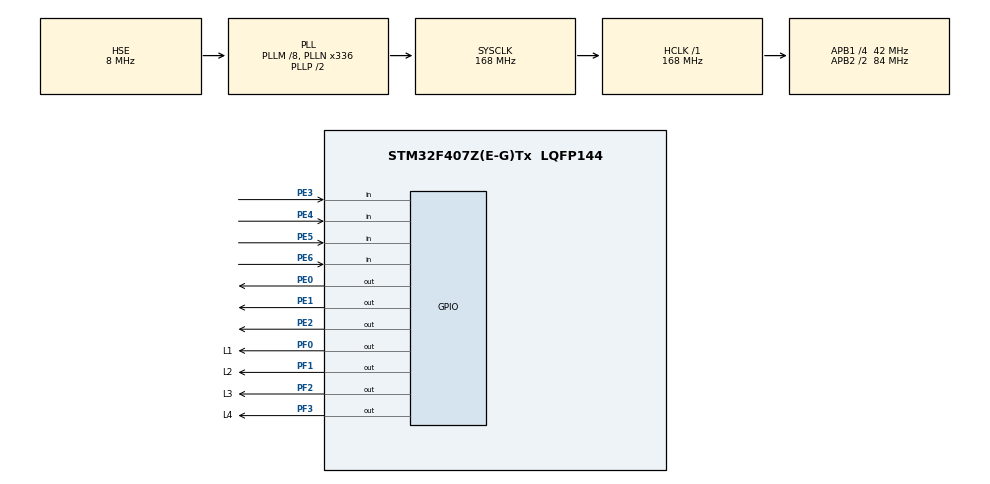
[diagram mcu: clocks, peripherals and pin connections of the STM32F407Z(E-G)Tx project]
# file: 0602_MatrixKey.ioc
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Mcu.Family=STM32F4
Mcu.Name=STM32F407Z(E-G)Tx
Mcu.Package=LQFP144
NVIC.PriorityGroup=NVIC_PRIORITYGROUP_4
PA13.Mode=Serial_Wire
PA13.Signal=SYS_JTMS-SWDIO
PA14.Mode=Serial_Wire
PA14.Signal=SYS_JTCK-SWCLK
PE0.PinState=GPIO_PIN_SET
PE0.Signal=GPIO_Output
PE1.PinState=GPIO_PIN_SET
PE1.Signal=GPIO_Output
PE2.PinState=GPIO_PIN_SET
PE2.Signal=GPIO_Output
PE3.GPIO_PuPd=GPIO_PULLUP
PE3.Signal=GPIO_Input
PE4.GPIO_PuPd=GPIO_PULLUP
PE4.Signal=GPIO_Input
PE5.GPIO_PuPd=GPIO_PULLUP
PE5.Signal=GPIO_Input
PE6.GPIO_PuPd=GPIO_PULLUP
PE6.Signal=GPIO_Input
PF0.GPIO_Label=L1
PF0.PinState=GPIO_PIN_SET
PF0.Signal=GPIO_Output
PF1.GPIO_Label=L2
PF1.PinState=GPIO_PIN_SET
PF1.Signal=GPIO_Output
PF2.GPIO_Label=L3
PF2.PinState=GPIO_PIN_SET
PF2.Signal=GPIO_Output
PF3.GPIO_Label=L4
PF3.PinState=GPIO_PIN_SET
PF3.Signal=GPIO_Output
PH0-OSC_IN.Mode=HSE-External-Oscillator
PH0-OSC_IN.Signal=RCC_OSC_IN
PH1-OSC_OUT.Mode=HSE-External-Oscillator
PH1-OSC_OUT.Signal=RCC_OSC_OUT
ProjectManager.HeapSize=0x200
ProjectManager.StackSize=0x400
ProjectManager.TargetToolchain=STM32CubeIDE
RCC.48MHZClocksFreq_Value=84000000
RCC.AHBFreq_Value=168000000
RCC.APB1CLKDivider=RCC_HCLK_DIV4
RCC.APB1Freq_Value=42000000
RCC.APB1TimFreq_Value=84000000
RCC.APB2CLKDivider=RCC_HCLK_DIV2
RCC.APB2Freq_Value=84000000
RCC.APB2TimFreq_Value=168000000
RCC.CortexFreq_Value=168000000
RCC.HCLKFreq_Value=168000000
RCC.HSE_VALUE=8000000
RCC.HSI_VALUE=16000000
RCC.LSE_VALUE=32768
RCC.PLLM=4
RCC.PLLN=168
RCC.PLLSourceVirtual=RCC_PLLSOURCE_HSE
RCC.SYSCLKFreq_VALUE=168000000
RCC.SYSCLKSource=RCC_SYSCLKSOURCE_PLLCLK
RCC.VCOOutputFreq_Value=336000000
board=custom

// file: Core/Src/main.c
/* USER CODE BEGIN Header */
/**
  ******************************************************************************
  * @file           : main.c
  * @brief          : 0602 MatrixKey 3×4矩阵键盘 → PF口LED输出421‑BCD
  *                 行：PE4 PE5 PE6    列：PE0 PE1 PE2 PE3
  *                 PF0~PF3 BCD输出，LED低电平点亮
  ******************************************************************************
  */
/* USER CODE END Header */
#include "main.h"

/* USER CODE BEGIN PV */
static uint8_t KeyVal = 0;
/* USER CODE END PV */

void SystemClock_Config(void);
static void MX_GPIO_Init(void);
/* USER CODE BEGIN PFP */
static void MatrixKey_Scan(void);
/* USER CODE END PFP */

/* USER CODE BEGIN 0 */

/**
 * @brief 3×4矩阵键盘扫描
 * 行：PE4、PE5、PE6
 * 列：PE0、PE1、PE2、PE3（上拉输入）
 * PF0-PF3输出BCD，低电平点亮LED
 */
static void MatrixKey_Scan(void)
{
    uint8_t i;
    uint16_t colState;

    // 依次扫描3行
    for(i = 0; i < 3; i++)
    {
        // 全部行先拉高
        HAL_GPIO_WritePin(GPIOE, GPIO_PIN_4|GPIO_PIN_5|GPIO_PIN_6, GPIO_PIN_SET);
        // 拉低当前行
        if(i == 0) HAL_GPIO_WritePin(GPIOE, GPIO_PIN_4, GPIO_PIN_RESET);
        if(i == 1) HAL_GPIO_WritePin(GPIOE, GPIO_PIN_5, GPIO_PIN_RESET);
        if(i == 2) HAL_GPIO_WritePin(GPIOE, GPIO_PIN_6, GPIO_PIN_RESET);

        HAL_Delay(5);
        colState = GPIOE->IDR & 0x0FU;

        if(colState != 0x0FU)
        {
            HAL_Delay(16);  //消抖
            colState = GPIOE->IDR & 0x0FU;
            if(colState != 0x0FU)
            {
                switch(colState)
                {
                    case 0x0E: KeyVal = i*4 + 1; break;  //PE0按下
                    case 0x0D: KeyVal = i*4 + 2; break;  //PE1按下
                    case 0x0B: KeyVal = i*4 + 3; break;  //PE2按下
                    case 0x07: KeyVal = i*4 + 4; break;  //PE3按下
                    default: break;
                }
                //等待松手
                while( (GPIOE->IDR & 0x0FU) != 0x0FU );
                HAL_Delay(10);
            }
        }
    }

    // PF4~PF7保持不变，PF0~PF3输出BCD，低亮
    GPIOF->ODR = (GPIOF->ODR & 0xF0U) | ( ~KeyVal & 0x0FU );
}

/* USER CODE END 0 */

int main(void)
{

  /* MCU Configuration--------------------------------------------------------*/

  /* Reset of all peripherals, Initializes the Flash interface and the Systick. */
  HAL_Init();

  /* Configure the system clock */
  SystemClock_Config();

  /* Initialize all configured peripherals */
  MX_GPIO_Init();

  /* Infinite loop */
  /* USER CODE BEGIN WHILE */
  while (1)
  {
    MatrixKey_Scan();
    /* USER CODE END WHILE */

  }
}

void SystemClock_Config(void)
{
  RCC_OscInitTypeDef RCC_OscInitStruct = {0};
  RCC_ClkInitTypeDef RCC_ClkInitStruct = {0};

  __HAL_RCC_PWR_CLK_ENABLE();
  __HAL_PWR_VOLTAGESCALING_CONFIG(PWR_REGULATOR_VOLTAGE_SCALE1);

  RCC_OscInitStruct.OscillatorType      = RCC_OSCILLATORTYPE_HSE;
  RCC_OscInitStruct.HSEState            = RCC_HSE_ON;
  RCC_OscInitStruct.PLL.PLLState        = RCC_PLL_ON;
  RCC_OscInitStruct.PLL.PLLSource       = RCC_PLLSOURCE_HSE;
  RCC_OscInitStruct.PLL.PLLM            = 8;
  RCC_OscInitStruct.PLL.PLLN            = 336;
  RCC_OscInitStruct.PLL.PLLP           = RCC_PLLP_DIV2;
  RCC_OscInitStruct.PLL.PLLQ            = 7;
  if (HAL_RCC_OscConfig(&RCC_OscInitStruct) != HAL_OK)
  {
    Error_Handler();
  }

  RCC_ClkInitStruct.ClockType           = RCC_CLOCKTYPE_HCLK|RCC_CLOCKTYPE_SYSCLK
                                          |RCC_CLOCKTYPE_PCLK1|RCC_CLOCKTYPE_PCLK2;
  RCC_ClkInitStruct.SYSCLKSource        = RCC_SYSCLKSOURCE_PLLCLK;
  RCC_ClkInitStruct.AHBCLKDivider       = RCC_SYSCLK_DIV1;
  RCC_ClkInitStruct.APB1CLKDivider      = RCC_HCLK_DIV4;
  RCC_ClkInitStruct.APB2CLKDivider      = RCC_HCLK_DIV2;

  if (HAL_RCC_ClockConfig(&RCC_ClkInitStruct, FLASH_LATENCY_5) != HAL_OK)
  {
    Error_Handler();
  }
}

static void MX_GPIO_Init(void)
{
  GPIO_InitTypeDef GPIO_InitStruct = {0};

  __HAL_RCC_GPIOE_CLK_ENABLE();
  __HAL_RCC_GPIOF_CLK_ENABLE();

  // PE0‑PE3 上拉输入（列）
  GPIO_InitStruct.Pin  = GPIO_PIN_0|GPIO_PIN_1|GPIO_PIN_2|GPIO_PIN_3;
  GPIO_InitStruct.Mode = GPIO_MODE_INPUT;
  GPIO_InitStruct.Pull = GPIO_PULLUP;
  HAL_GPIO_Init(GPIOE, &GPIO_InitStruct);

  // PE4‑PE6 推挽输出（行），初始高
  GPIO_InitStruct.Pin   = GPIO_PIN_4|GPIO_PIN_5|GPIO_PIN_6;
  GPIO_InitStruct.Mode  = GPIO_MODE_OUTPUT_PP;
  GPIO_InitStruct.Pull  = GPIO_NOPULL;
  GPIO_InitStruct.Speed = GPIO_SPEED_FREQ_LOW;
  HAL_GPIO_WritePin(GPIOE, GPIO_PIN_4|GPIO_PIN_5|GPIO_PIN_6, GPIO_PIN_SET);
  HAL_GPIO_Init(GPIOE, &GPIO_InitStruct);

  // PF0‑PF7 推挽输出，初始高
  GPIO_InitStruct.Pin   = GPIO_PIN_0|GPIO_PIN_1|GPIO_PIN_2|GPIO_PIN_3
                        |GPIO_PIN_4|GPIO_PIN_5|GPIO_PIN_6|GPIO_PIN_7;
  GPIO_InitStruct.Mode  = GPIO_MODE_OUTPUT_PP;
  GPIO_InitStruct.Pull  = GPIO_NOPULL;
  GPIO_InitStruct.Speed = GPIO_SPEED_FREQ_LOW;
  HAL_GPIO_WritePin(GPIOF, GPIO_PIN_0|GPIO_PIN_1|GPIO_PIN_2|GPIO_PIN_3
                        |GPIO_PIN_4|GPIO_PIN_5|GPIO_PIN_6|GPIO_PIN_7, GPIO_PIN_SET);
  HAL_GPIO_Init(GPIOF, &GPIO_InitStruct);
}

void Error_Handler(void)
{
  __disable_irq();
  while (1)
  {
  }
}
